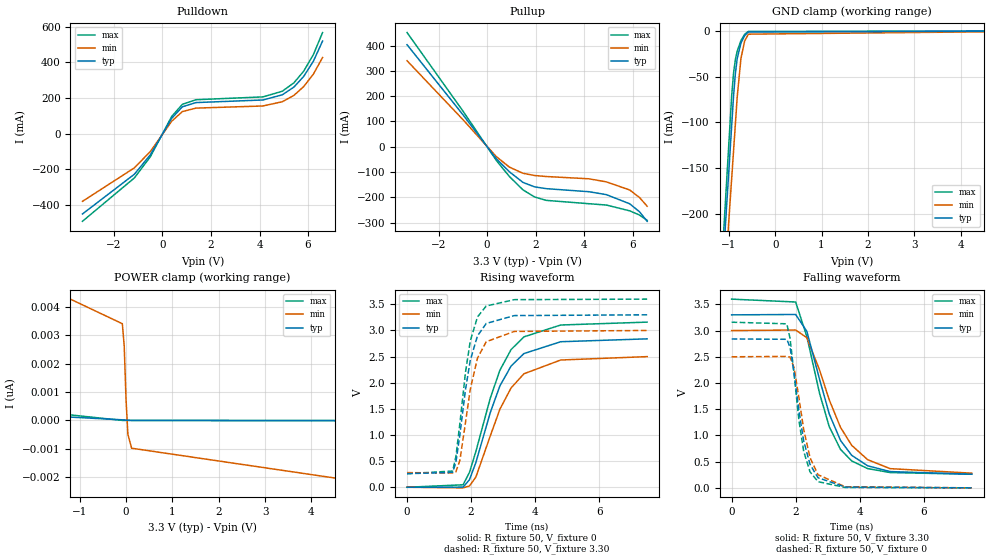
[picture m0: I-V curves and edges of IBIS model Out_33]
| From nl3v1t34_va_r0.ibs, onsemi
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|//////////////////////////////////////////////////////////////////////////////
|//////////////////////////////////////////////////////////////////////////////
[Model] Out_33
Model_type 3-state
Polarity Non-Inverting
Enable Active-Low
Vmeas = 1.65
Vref = 3.30
Rref = 2k
Cref = 15pF
|  variable   typ   min   max
C_comp   5.9pF   5.9pF   5.9pF
|//////////////////////////////////////////////////////////////////////////////
[Temperature Range]   25   125   -40
|//////////////////////////////////////////////////////////////////////////////
[Voltage Range]   3.30V   3.00V   3.60V
|//////////////////////////////////////////////////////////////////////////////
[Pulldown Reference]   0V   0V   0V
|//////////////////////////////////////////////////////////////////////////////
[Pullup Reference]   3.30V   3.00V   3.60V
|//////////////////////////////////////////////////////////////////////////////
[GND Clamp Reference]   0V   0V   0V
|//////////////////////////////////////////////////////////////////////////////
[POWER Clamp Reference] 3.30V   3.00V   3.60V
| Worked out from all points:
|   slope of the pulldown table from 0 to 0.495 V, typ, clamps not added: 4.55 ohm
|   slope of the pullup table from 0 to 0.495 V, typ, clamps not added: 8.21 ohm
|   GND clamp passes 1 mA (typ) near -0.56 V on its own axis
|   falling waveform, R_fixture 50, V_fixture 3.30: 20-80 % time 946ps typ, 1.1ns min, 883ps max; typ from 3.3 V to 0.26 V
|   falling waveform, R_fixture 50, V_fixture 0: 20-80 % time 446ps typ, 457ps min, 385ps max; typ from 2.84 V to 0 V
|   rising waveform, R_fixture 50, V_fixture 0: 20-80 % time 997ps typ, 1.03ns min, 1.01ns max; typ from 0 V to 2.84 V
|   rising waveform, R_fixture 50, V_fixture 3.30: 20-80 % time 456ps typ, 459ps min, 425ps max; typ from 0.26 V to 3.3 V
|//////////////////////////////////////////////////////////////////////////////
[Pulldown]
|   Voltage   I(typ)   I(min)   I(max)
-3.3V     -449.3mA   -378.6mA   -490.3mA
-1.16V    -226.7mA   -191mA     -247.4mA
-500mV    -117.8mA   -99.23mA   -128.5mA
380mV     86.7mA     70.36mA    97.2mA
820mV     151.1mA    124.2mA    164.9mA
1.38V     174.7mA    143.7mA    190.7mA
4.14V     189.2mA    155.6mA    206.5mA
4.94V     218.2mA    179.4mA    238.1mA
5.42V     261.7mA    215.2mA    285.6mA
5.82V     321mA      264mA      350.3mA
6.22V     406.1mA    334mA      443.2mA
6.6V      519.4mA    427.1mA    566.8mA
|//////////////////////////////////////////////////////////////////////////////
[Pullup]
|   Voltage   I(typ)   I(min)   I(max)
-3.3V     403.6mA    340.2mA    451.6mA
-980mV    124.8mA    105.7mA    139.2mA
380mV     -47.6mA    -39.05mA   -54.12mA
920mV     -99.06mA   -80.57mA   -117.8mA
1.48V     -141.1mA   -105mA     -170.6mA
1.96V     -158.7mA   -113.8mA   -198.7mA
2.44V     -165.8mA   -117.8mA   -212.1mA
4.2V      -177.9mA   -126.8mA   -225.4mA
4.92V     -189.5mA   -139mA     -230.6mA
5.88V     -225.6mA   -171mA     -253.5mA
6.28V     -256.9mA   -200.5mA   -270mA
6.6V      -294.9mA   -235.2mA   -291.1mA
|//////////////////////////////////////////////////////////////////////////////
[GND Clamp]
|   Voltage   I(typ)   I(min)   I(max)
-3.3V     -2.005A    -1.921A    -2.113A
-1.18V    -297.1mA   -340.5mA   -277.8mA
-1.1V     -232.7mA   -280.8mA   -208.6mA
-1.04V    -184.3mA   -236.1mA   -156.7mA
-940mV    -103.8mA   -161.5mA   -71.06mA
-900mV    -71.57mA   -131.7mA   -46.56mA
-860mV    -46.57mA   -101.9mA   -31.39mA
-820mV    -30.09mA   -72.06mA   -22.12mA
-740mV    -13.38mA   -30.24mA   -10.68mA
-660mV    -5.326mA   -11.19mA   -3.739mA
-580mV    -1.331mA   -3.661mA   -656.1uA
6.6V      -4.579pA   6.697pA    2.174pA
|//////////////////////////////////////////////////////////////////////////////
[POWER Clamp]
|   Voltage   I(typ)   I(min)   I(max)
-3.3V     43.79nA    47.37nA    66.8nA
-2.6V     6.017nA    10.84nA    10.2nA
-2.4V     3.201nA    8.048nA    5.628nA
-2.2V     1.652nA    6.457nA    3.005nA
-2V       828.2pA    5.533nA    1.547nA
-1.5V     141.8pA    4.504nA    245.3pA
-80mV     20.18pA    3.407nA    -386.2fA
-40mV     16.17pA    2.629nA    -421.3fA
0V        11.07pA    715.9pA    -456.3fA
40mV      5.858pA    -496.3pA   -491.4fA
120mV     -1.423pA   -980.5pA   -561.5fA
6.6V      -14.66pA   -2.533nA   -6.243pA
|//////////////////////////////////////////////////////////////////////////////
|//////////////////////////////////////////////////////////////////////////////
[Ramp]
|  variable   typ   min   max
dV/dt_f   1.824E+00/9.500E-10  1.632E+00/1.100E-09  2.004E+00/9.000E-10
dV/dt_r   1.704E+00/1.000E-09  1.500E+00/1.050E-09  1.896E+00/1.000E-09
R_load = 50
|/////////////////////////////////////////////////////////////////////////////
[Falling Waveform]
R_fixture = 50
V_fixture = 3.30
V_fixture_min = 3.00
V_fixture_max = 3.60
C_fixture = 0p
|   time   V(typ)   V(min)   V(max)
0s        3.3V       3V         3.6V
2ns       3.307V     3.011V     3.545V
2.35ns    2.985V     2.864V     2.885V
2.75ns    2.063V     2.243V     1.795V
3.05ns    1.41V      1.677V     1.166V
3.4ns     905.1mV    1.155V     734.3mV
3.75ns    620.4mV    811.4mV    513.6mV
4.25ns    420.4mV    536.8mV    367.6mV
4.95ns    310.7mV    366.9mV    291.9mV
7.5ns     260mV      280mV      260mV
|//////////////////////////////////////////////////////////////////////////////
[Falling Waveform]
R_fixture = 50
V_fixture = 0
C_fixture = 0p
|   time   V(typ)   V(min)   V(max)
0s        2.84V      2.5V       3.16V
1.725ns   2.834V     2.507V     3.129V
1.825ns   2.681V     2.494V     2.852V
1.95ns    2.201V     2.291V     2.173V
2.1ns     1.48V      1.727V     1.3V
2.25ns    898.8mV    1.117V     699mV
2.45ns    445.1mV    574.2mV    304.4mV
2.7ns     192.6mV    249.7mV    117.3mV
3.55ns    16.43mV    20.96mV    7.345mV
7.5ns     0V         0V         0V
|//////////////////////////////////////////////////////////////////////////////
[Rising Waveform]
R_fixture = 50
V_fixture = 0
C_fixture = 0p
|   time   V(typ)   V(min)   V(max)
0s        0V         0V         0V
1.75ns    2.198mV    -11.46mV   47.19mV
1.95ns    145.1mV    24.65mV    284.6mV
2.15ns    473.3mV    195.2mV    684.3mV
2.6ns     1.43V      982.5mV    1.705V
2.9ns     1.939V     1.493V     2.239V
3.25ns    2.32V      1.901V     2.635V
3.65ns    2.558V     2.171V     2.878V
4.8ns     2.785V     2.435V     3.105V
7.5ns     2.84V      2.5V       3.16V
|//////////////////////////////////////////////////////////////////////////////
[Rising Waveform]
R_fixture = 50
V_fixture = 3.30
V_fixture_min = 3.00
V_fixture_max = 3.60
C_fixture = 0p
|   time   V(typ)   V(min)   V(max)
0s        260mV      280mV      260mV
1.425ns   284.8mV    273.2mV    310.5mV
1.525ns   477.4mV    293.9mV    581.6mV
1.65ns    997.5mV    514.8mV    1.218V
1.825ns   1.865V     1.237V     2.197V
1.975ns   2.428V     1.874V     2.798V
2.2ns     2.898V     2.471V     3.258V
2.475ns   3.135V     2.786V     3.469V
3.35ns    3.285V     2.982V     3.59V
7.5ns     3.3V       3V         3.6V
